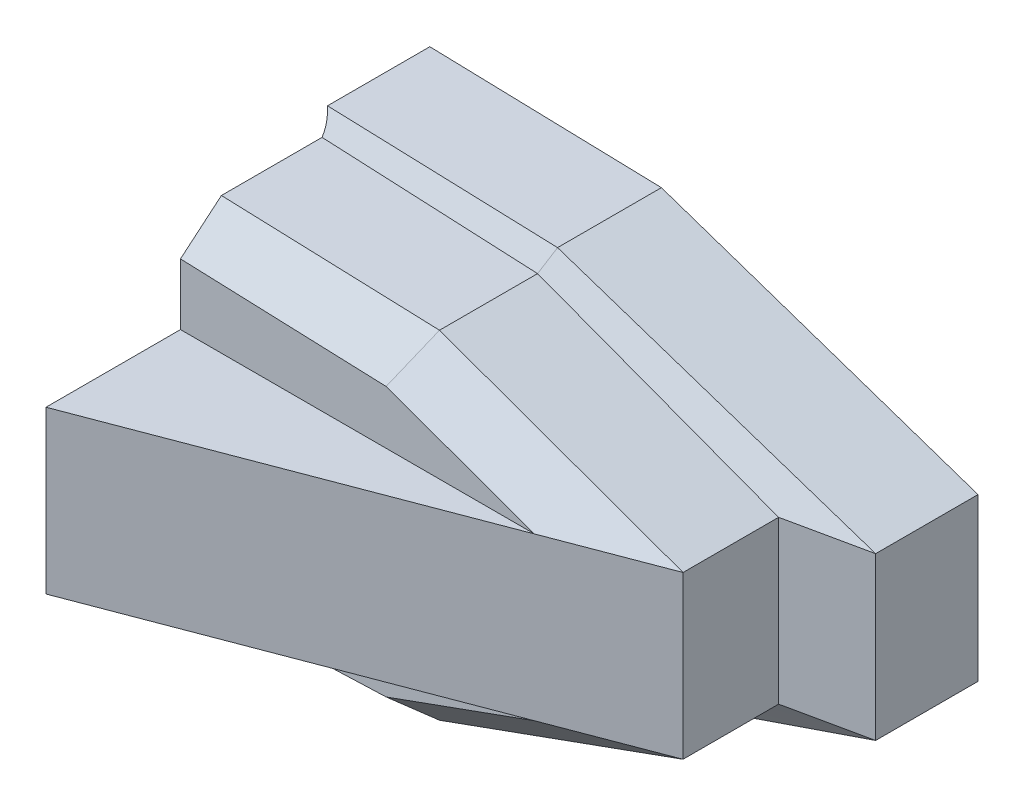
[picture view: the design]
ISO-10303-21;
HEADER;
FILE_DESCRIPTION(('STEP AP214'),'2;1');
FILE_NAME('part.step','',(''),(''),'','','');
FILE_SCHEMA(('AUTOMOTIVE_DESIGN { 1 0 10303 214 1 1 1 1 }'));
ENDSEC;
DATA;
#1=APPLICATION_CONTEXT('core data for automotive mechanical design processes');
#2=APPLICATION_PROTOCOL_DEFINITION('international standard','automotive_design',2000,#1);
#3=PRODUCT_CONTEXT('',#1,'mechanical');
#4=PRODUCT('Part','Part','',(#3));
#5=PRODUCT_RELATED_PRODUCT_CATEGORY('part','',(#4));
#6=PRODUCT_DEFINITION_FORMATION('','',#4);
#7=PRODUCT_DEFINITION_CONTEXT('part definition',#1,'design');
#8=PRODUCT_DEFINITION('design','',#6,#7);
#9=PRODUCT_DEFINITION_SHAPE('','',#8);
#10=(LENGTH_UNIT() NAMED_UNIT(*) SI_UNIT(.MILLI.,.METRE.));
#11=(NAMED_UNIT(*) PLANE_ANGLE_UNIT() SI_UNIT($,.RADIAN.));
#12=(NAMED_UNIT(*) SI_UNIT($,.STERADIAN.) SOLID_ANGLE_UNIT());
#13=UNCERTAINTY_MEASURE_WITH_UNIT(LENGTH_MEASURE(1.E-05),#10,'distance_accuracy_value','');
#14=(GEOMETRIC_REPRESENTATION_CONTEXT(3) GLOBAL_UNCERTAINTY_ASSIGNED_CONTEXT((#13)) GLOBAL_UNIT_ASSIGNED_CONTEXT((#10,
#11,#12)) REPRESENTATION_CONTEXT('',''));
#15=CARTESIAN_POINT('',(0.,0.,0.));
#16=DIRECTION('',(0.,0.,1.));
#17=DIRECTION('',(1.,0.,0.));
#18=AXIS2_PLACEMENT_3D('',#15,#16,#17);
#19=CARTESIAN_POINT('',(0.,158.06960654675,0.));
#20=DIRECTION('',(0.,-1.,0.));
#21=DIRECTION('',(0.,0.,-1.));
#22=AXIS2_PLACEMENT_3D('',#19,#20,#21);
#23=PLANE('',#22);
#24=DIRECTION('',(0.,0.,-1.));
#25=VECTOR('',#24,1.);
#26=CARTESIAN_POINT('',(1530.,158.06960654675,0.));
#27=LINE('',#26,#25);
#28=CARTESIAN_POINT('',(1530.,158.06960654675,762.78272385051));
#29=VERTEX_POINT('',#28);
#30=CARTESIAN_POINT('',(1530.,158.06960654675,500.));
#31=VERTEX_POINT('',#30);
#32=EDGE_CURVE('E68',#29,#31,#27,.T.);
#33=ORIENTED_EDGE('',*,*,#32,.F.);
#34=DIRECTION('',(-0.934788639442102,0.,0.355204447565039));
#35=VECTOR('',#34,1.);
#36=CARTESIAN_POINT('',(430.6727342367,158.06960654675,1180.509167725));
#37=LINE('',#36,#35);
#38=CARTESIAN_POINT('',(2221.563145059,158.06960654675,500.));
#39=VERTEX_POINT('',#38);
#40=EDGE_CURVE('E1070',#39,#29,#37,.T.);
#41=ORIENTED_EDGE('',*,*,#40,.F.);
#42=DIRECTION('',(1.,0.,0.));
#43=VECTOR('',#42,1.);
#44=CARTESIAN_POINT('',(0.,158.06960654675,500.));
#45=LINE('',#44,#43);
#46=EDGE_CURVE('E11',#31,#39,#45,.T.);
#47=ORIENTED_EDGE('',*,*,#46,.F.);
#48=EDGE_LOOP('',(#33,#41,#47));
#49=FACE_BOUND('',#48,.T.);
#50=ADVANCED_FACE('F46',(#49),#23,.F.);
#51=CARTESIAN_POINT('',(0.,0.,500.));
#52=DIRECTION('',(0.,0.,1.));
#53=DIRECTION('',(1.,0.,0.));
#54=AXIS2_PLACEMENT_3D('',#51,#52,#53);
#55=PLANE('',#54);
#56=ORIENTED_EDGE('',*,*,#46,.T.);
#57=DIRECTION('',(0.94052400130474,-0.339727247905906,0.));
#58=VECTOR('',#57,1.);
#59=CARTESIAN_POINT('',(2076.689498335,210.39950480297,500.));
#60=LINE('',#59,#58);
#61=CARTESIAN_POINT('',(1931.81585161,262.72940305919,500.));
#62=VERTEX_POINT('',#61);
#63=EDGE_CURVE('E858',#62,#39,#60,.T.);
#64=ORIENTED_EDGE('',*,*,#63,.F.);
#65=DIRECTION('',(0.999303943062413,-0.037304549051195,0.));
#66=VECTOR('',#65,1.);
#67=CARTESIAN_POINT('',(1530.,277.729403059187,500.));
#68=LINE('',#67,#66);
#69=CARTESIAN_POINT('',(1530.,277.72940305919,500.));
#70=VERTEX_POINT('',#69);
#71=EDGE_CURVE('E869',#70,#62,#68,.T.);
#72=ORIENTED_EDGE('',*,*,#71,.F.);
#73=DIRECTION('',(0.,-1.,0.));
#74=VECTOR('',#73,1.);
#75=CARTESIAN_POINT('',(1530.,-1.79233E-12,500.));
#76=LINE('',#75,#74);
#77=EDGE_CURVE('E59',#70,#31,#76,.T.);
#78=ORIENTED_EDGE('',*,*,#77,.T.);
#79=EDGE_LOOP('',(#56,#64,#72,#78));
#80=FACE_BOUND('',#79,.T.);
#81=ADVANCED_FACE('F404',(#80),#55,.T.);
#82=CARTESIAN_POINT('',(1517.2,-360.,450.));
#83=DIRECTION('',(-1.,0.,0.));
#84=DIRECTION('',(0.,0.,1.));
#85=AXIS2_PLACEMENT_3D('',#82,#83,#84);
#86=PLANE('',#85);
#87=DIRECTION('',(0.,0.707106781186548,0.707106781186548));
#88=VECTOR('',#87,1.);
#89=CARTESIAN_POINT('',(1517.2,135.,-44.99999999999));
#90=LINE('',#89,#88);
#91=CARTESIAN_POINT('',(1517.2,330.,150.));
#92=VERTEX_POINT('',#91);
#93=CARTESIAN_POINT('',(1517.2,380.08734023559,200.08734023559));
#94=VERTEX_POINT('',#93);
#95=EDGE_CURVE('E1067',#92,#94,#90,.T.);
#96=ORIENTED_EDGE('',*,*,#95,.T.);
#97=DIRECTION('',(3.57204538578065E-12,0.832000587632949,-0.554774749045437));
#98=VECTOR('',#97,1.);
#99=CARTESIAN_POINT('',(1517.2,380.087340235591,200.087340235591));
#100=LINE('',#99,#98);
#101=CARTESIAN_POINT('',(1517.2,380.34593331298,199.91491137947));
#102=VERTEX_POINT('',#101);
#103=EDGE_CURVE('E1074',#94,#102,#100,.T.);
#104=ORIENTED_EDGE('',*,*,#103,.T.);
#105=DIRECTION('',(0.,0.,1.));
#106=VECTOR('',#105,1.);
#107=CARTESIAN_POINT('',(1517.2,380.34593331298,450.));
#108=LINE('',#107,#106);
#109=CARTESIAN_POINT('',(1517.2,380.34593331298,0.));
#110=VERTEX_POINT('',#109);
#111=EDGE_CURVE('E875',#110,#102,#108,.T.);
#112=ORIENTED_EDGE('',*,*,#111,.F.);
#113=DIRECTION('',(0.,-1.,0.));
#114=VECTOR('',#113,1.);
#115=CARTESIAN_POINT('',(1517.2,-2.02662E-12,0.));
#116=LINE('',#115,#114);
#117=CARTESIAN_POINT('',(1517.2,330.,0.));
#118=VERTEX_POINT('',#117);
#119=EDGE_CURVE('E1058',#110,#118,#116,.T.);
#120=ORIENTED_EDGE('',*,*,#119,.T.);
#121=DIRECTION('',(0.,0.,1.));
#122=VECTOR('',#121,1.);
#123=CARTESIAN_POINT('',(1517.2,330.,450.));
#124=LINE('',#123,#122);
#125=EDGE_CURVE('E110',#118,#92,#124,.T.);
#126=ORIENTED_EDGE('',*,*,#125,.T.);
#127=EDGE_LOOP('',(#96,#104,#112,#120,#126));
#128=FACE_BOUND('',#127,.T.);
#129=ADVANCED_FACE('F409',(#128),#86,.T.);
#130=CARTESIAN_POINT('',(1529.95786937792,345.001483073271,420.));
#131=CARTESIAN_POINT('',(1529.95867019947,322.577950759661,446.66666666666));
#132=CARTESIAN_POINT('',(1529.95947102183,300.154418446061,473.33333333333));
#133=CARTESIAN_POINT('',(1529.96027184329,277.730886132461,500.));
#134=CARTESIAN_POINT('',(1672.01014789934,340.000988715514,420.));
#135=CARTESIAN_POINT('',(1669.31080918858,317.577456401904,446.66666666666));
#136=CARTESIAN_POINT('',(1666.61147047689,295.153924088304,473.33333333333));
#137=CARTESIAN_POINT('',(1663.91213176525,272.730391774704,500.));
#138=CARTESIAN_POINT('',(1814.06242642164,335.000494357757,420.));
#139=CARTESIAN_POINT('',(1808.66294817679,312.576962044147,446.66666666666));
#140=CARTESIAN_POINT('',(1803.26346993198,290.153429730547,473.33333333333));
#141=CARTESIAN_POINT('',(1797.8639916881,267.729897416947,500.));
#142=CARTESIAN_POINT('',(1956.114704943,330.,420.));
#143=CARTESIAN_POINT('',(1948.015087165,307.57646768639,446.66666666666));
#144=CARTESIAN_POINT('',(1939.915469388,285.15293537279,473.33333333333));
#145=CARTESIAN_POINT('',(1931.81585161,262.72940305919,500.));
#146=(BOUNDED_SURFACE() B_SPLINE_SURFACE(3,3,((#130,#131,#132,#133),(#134,#135,#136,#137),(#138,
#139,#140,#141),(#142,#143,#144,#145)),.UNSPECIFIED.,.F.,.F.,
.F.) B_SPLINE_SURFACE_WITH_KNOTS((4,4),(4,4),(0.0322699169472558,1.),(0.,1.),
.UNSPECIFIED.) GEOMETRIC_REPRESENTATION_ITEM() RATIONAL_B_SPLINE_SURFACE(((1.,1.,1.,1.),(1.,1.,
1.,1.),(1.,1.,1.,1.),(1.,1.,1.,1.))) REPRESENTATION_ITEM('') SURFACE());
#147=DIRECTION('',(0.226432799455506,0.626871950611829,-0.745492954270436));
#148=VECTOR('',#147,1.);
#149=CARTESIAN_POINT('',(1931.81585161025,262.729403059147,500.00000000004));
#150=LINE('',#149,#148);
#151=CARTESIAN_POINT('',(1956.114704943,329.99999999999,420.));
#152=VERTEX_POINT('',#151);
#153=EDGE_CURVE('E874',#62,#152,#150,.T.);
#154=DIRECTION('',(-0.999380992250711,0.0351799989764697,0.));
#155=VECTOR('',#154,1.);
#156=CARTESIAN_POINT('',(1956.114704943,329.999999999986,420.000000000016));
#157=LINE('',#156,#155);
#158=CARTESIAN_POINT('',(1530.,345.,420.));
#159=VERTEX_POINT('',#158);
#160=EDGE_CURVE('E871',#152,#159,#157,.T.);
#161=DIRECTION('',(0.,-0.643587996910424,0.765372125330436));
#162=VECTOR('',#161,1.);
#163=CARTESIAN_POINT('',(1530.,345.,420.));
#164=LINE('',#163,#162);
#165=EDGE_CURVE('E188',#159,#70,#164,.T.);
#166=ORIENTED_EDGE('',*,*,#71,.T.);
#167=ORIENTED_EDGE('',*,*,#153,.T.);
#168=ORIENTED_EDGE('',*,*,#160,.T.);
#169=ORIENTED_EDGE('',*,*,#165,.T.);
#170=EDGE_LOOP('',(#166,#167,#168,#169));
#171=FACE_BOUND('',#170,.T.);
#172=ADVANCED_FACE('F915',(#171),#146,.F.);
#173=CARTESIAN_POINT('',(2054.170903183,75.,563.60632371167));
#174=DIRECTION('',(0.355204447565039,0.,0.934788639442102));
#175=DIRECTION('',(0.,-1.,0.));
#176=AXIS2_PLACEMENT_3D('',#173,#174,#175);
#177=PLANE('',#176);
#178=DIRECTION('',(0.,1.,0.));
#179=VECTOR('',#178,1.);
#180=CARTESIAN_POINT('',(1530.,75.,762.78272385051));
#181=LINE('',#180,#179);
#182=CARTESIAN_POINT('',(1530.,-158.06960654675,762.78272385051));
#183=VERTEX_POINT('',#182);
#184=EDGE_CURVE('E774',#183,#29,#181,.T.);
#185=ORIENTED_EDGE('',*,*,#184,.F.);
#186=DIRECTION('',(-0.934788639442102,0.,0.355204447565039));
#187=VECTOR('',#186,1.);
#188=CARTESIAN_POINT('',(430.6727342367,-158.06960654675,1180.509167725));
#189=LINE('',#188,#187);
#190=CARTESIAN_POINT('',(2221.563145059,-158.06960654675,500.));
#191=VERTEX_POINT('',#190);
#192=EDGE_CURVE('E690',#191,#183,#189,.T.);
#193=ORIENTED_EDGE('',*,*,#192,.F.);
#194=DIRECTION('',(0.934788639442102,0.,-0.355204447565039));
#195=VECTOR('',#194,1.);
#196=CARTESIAN_POINT('',(2326.830817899,-158.06960654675,460.));
#197=LINE('',#196,#195);
#198=CARTESIAN_POINT('',(2432.09849074,-158.06960654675,420.));
#199=VERTEX_POINT('',#198);
#200=EDGE_CURVE('E724',#191,#199,#197,.T.);
#201=ORIENTED_EDGE('',*,*,#200,.T.);
#202=DIRECTION('',(0.,-1.,0.));
#203=VECTOR('',#202,1.);
#204=CARTESIAN_POINT('',(2432.09849074,74.999999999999,420.));
#205=LINE('',#204,#203);
#206=CARTESIAN_POINT('',(2432.09849074,158.06960654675,420.));
#207=VERTEX_POINT('',#206);
#208=EDGE_CURVE('E847',#207,#199,#205,.T.);
#209=ORIENTED_EDGE('',*,*,#208,.F.);
#210=DIRECTION('',(0.934788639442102,0.,-0.355204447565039));
#211=VECTOR('',#210,1.);
#212=CARTESIAN_POINT('',(2326.830817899,158.06960654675,460.));
#213=LINE('',#212,#211);
#214=EDGE_CURVE('E849',#39,#207,#213,.T.);
#215=ORIENTED_EDGE('',*,*,#214,.F.);
#216=ORIENTED_EDGE('',*,*,#40,.T.);
#217=EDGE_LOOP('',(#185,#193,#201,#209,#215,#216));
#218=FACE_BOUND('',#217,.T.);
#219=ADVANCED_FACE('F845',(#218),#177,.T.);
#220=CARTESIAN_POINT('',(0.,0.,0.));
#221=DIRECTION('',(0.,0.,1.));
#222=DIRECTION('',(1.,0.,0.));
#223=AXIS2_PLACEMENT_3D('',#220,#221,#222);
#224=PLANE('',#223);
#225=DIRECTION('',(0.,1.,0.));
#226=VECTOR('',#225,1.);
#227=CARTESIAN_POINT('',(2588.42339805,-191.9303934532,0.));
#228=LINE('',#227,#226);
#229=CARTESIAN_POINT('',(2588.42339805,-158.06960654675,0.));
#230=VERTEX_POINT('',#229);
#231=CARTESIAN_POINT('',(2588.42339805,158.06960654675,0.));
#232=VERTEX_POINT('',#231);
#233=EDGE_CURVE('E1040',#230,#232,#228,.T.);
#234=ORIENTED_EDGE('',*,*,#233,.F.);
#235=DIRECTION('',(0.946912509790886,0.321491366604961,0.));
#236=VECTOR('',#235,1.);
#237=CARTESIAN_POINT('',(2279.092211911,-263.09230371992,0.));
#238=LINE('',#237,#236);
#239=CARTESIAN_POINT('',(1969.761025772,-368.11500089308,0.));
#240=VERTEX_POINT('',#239);
#241=EDGE_CURVE('E705',#240,#230,#238,.T.);
#242=ORIENTED_EDGE('',*,*,#241,.F.);
#243=DIRECTION('',(-0.999634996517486,-0.0270161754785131,0.));
#244=VECTOR('',#243,1.);
#245=CARTESIAN_POINT('',(1752.008107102,-374.,0.));
#246=LINE('',#245,#244);
#247=CARTESIAN_POINT('',(1517.2,-380.34593331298,0.));
#248=VERTEX_POINT('',#247);
#249=EDGE_CURVE('E286',#240,#248,#246,.T.);
#250=ORIENTED_EDGE('',*,*,#249,.T.);
#251=DIRECTION('',(0.,1.,0.));
#252=VECTOR('',#251,1.);
#253=CARTESIAN_POINT('',(1517.2,2.02662E-12,0.));
#254=LINE('',#253,#252);
#255=CARTESIAN_POINT('',(1517.2,-330.,0.));
#256=VERTEX_POINT('',#255);
#257=EDGE_CURVE('E248',#248,#256,#254,.T.);
#258=ORIENTED_EDGE('',*,*,#257,.T.);
#259=DIRECTION('',(1.,0.,0.));
#260=VECTOR('',#259,1.);
#261=CARTESIAN_POINT('',(1480.,-330.,0.));
#262=LINE('',#261,#260);
#263=CARTESIAN_POINT('',(1530.,-330.,0.));
#264=VERTEX_POINT('',#263);
#265=EDGE_CURVE('E255',#256,#264,#262,.T.);
#266=ORIENTED_EDGE('',*,*,#265,.T.);
#267=DIRECTION('',(0.,-1.,0.));
#268=VECTOR('',#267,1.);
#269=CARTESIAN_POINT('',(1530.,-2.02662E-12,0.));
#270=LINE('',#269,#268);
#271=CARTESIAN_POINT('',(1530.,330.,0.));
#272=VERTEX_POINT('',#271);
#273=EDGE_CURVE('E175',#272,#264,#270,.T.);
#274=ORIENTED_EDGE('',*,*,#273,.F.);
#275=DIRECTION('',(1.,0.,0.));
#276=VECTOR('',#275,1.);
#277=CARTESIAN_POINT('',(1480.,330.,0.));
#278=LINE('',#277,#276);
#279=EDGE_CURVE('E211',#118,#272,#278,.T.);
#280=ORIENTED_EDGE('',*,*,#279,.F.);
#281=ORIENTED_EDGE('',*,*,#119,.F.);
#282=DIRECTION('',(-0.999634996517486,0.0270161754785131,0.));
#283=VECTOR('',#282,1.);
#284=CARTESIAN_POINT('',(1752.008107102,374.,0.));
#285=LINE('',#284,#283);
#286=CARTESIAN_POINT('',(1969.761025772,368.11500089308,0.));
#287=VERTEX_POINT('',#286);
#288=EDGE_CURVE('E856',#287,#110,#285,.T.);
#289=ORIENTED_EDGE('',*,*,#288,.F.);
#290=DIRECTION('',(0.946912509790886,-0.321491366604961,0.));
#291=VECTOR('',#290,1.);
#292=CARTESIAN_POINT('',(2279.092211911,263.09230371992,0.));
#293=LINE('',#292,#291);
#294=EDGE_CURVE('E1041',#287,#232,#293,.T.);
#295=ORIENTED_EDGE('',*,*,#294,.T.);
#296=EDGE_LOOP('',(#234,#242,#250,#258,#266,#274,#280,#281,#289,#295));
#297=FACE_BOUND('',#296,.T.);
#298=ADVANCED_FACE('F452',(#297),#224,.F.);
#299=CARTESIAN_POINT('',(2194.106597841,244.03480327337,420.));
#300=DIRECTION('',(0.253264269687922,0.701154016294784,0.666513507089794));
#301=DIRECTION('',(0.934788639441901,0.,-0.355204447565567));
#302=AXIS2_PLACEMENT_3D('',#299,#300,#301);
#303=PLANE('',#302);
#304=ORIENTED_EDGE('',*,*,#153,.F.);
#305=ORIENTED_EDGE('',*,*,#63,.T.);
#306=ORIENTED_EDGE('',*,*,#214,.T.);
#307=DIRECTION('',(-0.94052400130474,0.339727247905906,0.));
#308=VECTOR('',#307,1.);
#309=CARTESIAN_POINT('',(2194.106597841,244.03480327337,420.));
#310=LINE('',#309,#308);
#311=EDGE_CURVE('E853',#207,#152,#310,.T.);
#312=ORIENTED_EDGE('',*,*,#311,.T.);
#313=EDGE_LOOP('',(#304,#305,#306,#312));
#314=FACE_BOUND('',#313,.T.);
#315=ADVANCED_FACE('F448',(#314),#303,.T.);
#316=CARTESIAN_POINT('',(1752.008107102,374.,100.));
#317=DIRECTION('',(-0.0270161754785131,-0.999634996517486,0.));
#318=DIRECTION('',(-0.999634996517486,0.0270161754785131,0.));
#319=AXIS2_PLACEMENT_3D('',#316,#317,#318);
#320=PLANE('',#319);
#321=ORIENTED_EDGE('',*,*,#288,.T.);
#322=ORIENTED_EDGE('',*,*,#111,.T.);
#323=DIRECTION('',(0.999612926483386,-0.0270155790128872,0.00664497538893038));
#324=VECTOR('',#323,1.);
#325=CARTESIAN_POINT('',(1517.2,380.345933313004,199.914911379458));
#326=LINE('',#325,#324);
#327=CARTESIAN_POINT('',(1969.761025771,368.11500089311,202.92333273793));
#328=VERTEX_POINT('',#327);
#329=EDGE_CURVE('E200',#102,#328,#326,.T.);
#330=ORIENTED_EDGE('',*,*,#329,.T.);
#331=DIRECTION('',(0.,0.,1.));
#332=VECTOR('',#331,1.);
#333=CARTESIAN_POINT('',(1969.761025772,368.11500089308,100.));
#334=LINE('',#333,#332);
#335=EDGE_CURVE('E155',#287,#328,#334,.T.);
#336=ORIENTED_EDGE('',*,*,#335,.F.);
#337=EDGE_LOOP('',(#321,#322,#330,#336));
#338=FACE_BOUND('',#337,.T.);
#339=ADVANCED_FACE('F420',(#338),#320,.F.);
#340=CARTESIAN_POINT('',(1517.49815479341,345.440087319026,223.186637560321));
#341=CARTESIAN_POINT('',(1663.70367150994,340.293391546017,224.902202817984));
#342=CARTESIAN_POINT('',(1809.90918822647,335.146695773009,226.617768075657));
#343=CARTESIAN_POINT('',(1956.114704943,330.,228.33333333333));
#344=CARTESIAN_POINT('',(1517.36469762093,357.076290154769,215.42916900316));
#345=CARTESIAN_POINT('',(1665.13095793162,352.285860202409,216.90722371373));
#346=CARTESIAN_POINT('',(1812.89721824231,347.49543025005,218.3852784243));
#347=CARTESIAN_POINT('',(1960.663478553,342.70500029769,219.86333313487));
#348=CARTESIAN_POINT('',(1517.23124044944,368.712492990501,207.671700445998));
#349=CARTESIAN_POINT('',(1666.5582443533,364.278328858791,208.912244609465));
#350=CARTESIAN_POINT('',(1815.88524825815,359.844164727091,210.152788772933));
#351=CARTESIAN_POINT('',(1965.212252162,355.41000059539,211.3933329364));
#352=CARTESIAN_POINT('',(1517.09778327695,380.348695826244,199.914231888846));
#353=CARTESIAN_POINT('',(1667.98553077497,376.270797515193,200.917265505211));
#354=CARTESIAN_POINT('',(1818.87327827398,372.192899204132,201.920299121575));
#355=CARTESIAN_POINT('',(1969.761025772,368.11500089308,202.92333273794));
#356=(BOUNDED_SURFACE() B_SPLINE_SURFACE(3,3,((#340,#341,#342,#343),(#344,#345,#346,#347),(#348,
#349,#350,#351),(#352,#353,#354,#355)),.UNSPECIFIED.,.F.,.F.,
.F.) B_SPLINE_SURFACE_WITH_KNOTS((4,4),(4,4),(0.,1.),(0.00213433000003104,1.),
.UNSPECIFIED.) GEOMETRIC_REPRESENTATION_ITEM() RATIONAL_B_SPLINE_SURFACE(((1.,1.,1.,1.),(1.,1.,
1.,1.),(1.,1.,1.,1.),(1.,1.,1.,1.))) REPRESENTATION_ITEM('') SURFACE());
#357=CARTESIAN_POINT('',(1530.00000000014,344.99999999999,223.333333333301));
#358=CARTESIAN_POINT('',(1530.0003825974,345.615165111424,222.923130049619));
#359=CARTESIAN_POINT('',(1529.98952146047,346.23044366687,222.5130349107));
#360=CARTESIAN_POINT('',(1529.93410270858,347.774901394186,221.48402706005));
#361=CARTESIAN_POINT('',(1529.87516331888,348.703836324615,220.865483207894));
#362=CARTESIAN_POINT('',(1529.71118224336,350.505502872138,219.666378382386));
#363=CARTESIAN_POINT('',(1529.60898115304,351.378399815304,219.085675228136));
#364=CARTESIAN_POINT('',(1529.39035597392,352.90641193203,218.069462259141));
#365=CARTESIAN_POINT('',(1529.28355959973,353.56246037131,217.633255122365));
#366=CARTESIAN_POINT('',(1529.01004400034,355.061548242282,216.637024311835));
#367=CARTESIAN_POINT('',(1528.83492909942,355.903605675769,216.077802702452));
#368=CARTESIAN_POINT('',(1528.45605640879,357.527040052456,215.000095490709));
#369=CARTESIAN_POINT('',(1528.2548785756,358.30882400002,214.481311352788));
#370=CARTESIAN_POINT('',(1527.83239131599,359.811405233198,213.484478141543));
#371=CARTESIAN_POINT('',(1527.61345924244,360.532658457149,213.006108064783));
#372=CARTESIAN_POINT('',(1527.16336886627,361.914141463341,212.090120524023));
#373=CARTESIAN_POINT('',(1526.93439170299,362.574856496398,211.652160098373));
#374=CARTESIAN_POINT('',(1526.39841160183,364.034416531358,210.685277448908));
#375=CARTESIAN_POINT('',(1526.08531071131,364.831771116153,210.157474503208));
#376=CARTESIAN_POINT('',(1525.43004646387,366.399486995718,209.120318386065));
#377=CARTESIAN_POINT('',(1525.08863793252,367.170062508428,208.61081110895));
#378=CARTESIAN_POINT('',(1524.38022542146,368.683874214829,207.610232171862));
#379=CARTESIAN_POINT('',(1524.01393889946,369.427340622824,207.119000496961));
#380=CARTESIAN_POINT('',(1523.25914691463,370.886709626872,206.154982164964));
#381=CARTESIAN_POINT('',(1522.87132526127,371.602856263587,205.682029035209));
#382=CARTESIAN_POINT('',(1522.07673341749,373.00748392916,204.754571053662));
#383=CARTESIAN_POINT('',(1521.67061647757,373.69622059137,204.299893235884));
#384=CARTESIAN_POINT('',(1520.84258639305,375.046036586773,203.408991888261));
#385=CARTESIAN_POINT('',(1520.42129845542,375.707381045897,202.972588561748));
#386=CARTESIAN_POINT('',(1519.56595448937,377.002514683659,202.11823931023));
#387=CARTESIAN_POINT('',(1519.13249758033,377.636576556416,201.700106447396));
#388=CARTESIAN_POINT('',(1518.25570142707,378.877351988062,200.882312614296));
#389=CARTESIAN_POINT('',(1517.81293708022,379.484343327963,200.482456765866));
#390=CARTESIAN_POINT('',(1517.36024682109,380.086246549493,200.086246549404));
#391=B_SPLINE_CURVE_WITH_KNOTS('',3,(#357,#358,#359,#360,#361,#362,#363,#364,#365,#366,#367,
#368,#369,#370,#371,#372,#373,#374,#375,#376,#377,#378,#379,#380,#381,#382,#383,#384,#385,#386,
#387,#388,#389,#390),.UNSPECIFIED.,.F.,.F.,(4,2,2,2,2,2,2,2,2,2,2,2,2,2,2,2,4),(0.,
2.21815423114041,5.56968175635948,8.72882319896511,11.1135594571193,14.1903090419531,
17.0683700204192,19.7460189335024,22.220909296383,25.2386554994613,28.1925694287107,
31.0822905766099,33.9071087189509,36.6660166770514,39.3577627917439,41.9809015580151,
44.5338412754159),.UNSPECIFIED.);
#392=CARTESIAN_POINT('',(1530.,344.99999999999,223.33333333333));
#393=VERTEX_POINT('',#392);
#394=CARTESIAN_POINT('',(1517.360246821,380.08624654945,200.08624654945));
#395=VERTEX_POINT('',#394);
#396=EDGE_CURVE('E161',#393,#395,#391,.T.);
#397=DIRECTION('',(0.999312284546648,-0.0351775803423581,0.0117258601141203));
#398=VECTOR('',#397,1.);
#399=CARTESIAN_POINT('',(1530.,344.999999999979,223.333333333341));
#400=LINE('',#399,#398);
#401=CARTESIAN_POINT('',(1956.114704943,330.,228.33333333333));
#402=VERTEX_POINT('',#401);
#403=EDGE_CURVE('E166',#393,#402,#400,.T.);
#404=DIRECTION('',(0.285500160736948,0.797419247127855,-0.531612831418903));
#405=VECTOR('',#404,1.);
#406=CARTESIAN_POINT('',(1969.761025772,368.11500089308,202.92333273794));
#407=LINE('',#406,#405);
#408=EDGE_CURVE('E201',#402,#328,#407,.T.);
#409=DIRECTION('',(0.999953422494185,-0.00682469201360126,-0.00682469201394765));
#410=VECTOR('',#409,1.);
#411=CARTESIAN_POINT('',(1517.2,380.08734023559,200.087340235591));
#412=LINE('',#411,#410);
#413=EDGE_CURVE('E168',#94,#395,#412,.T.);
#414=ORIENTED_EDGE('',*,*,#396,.F.);
#415=ORIENTED_EDGE('',*,*,#403,.T.);
#416=ORIENTED_EDGE('',*,*,#408,.T.);
#417=ORIENTED_EDGE('',*,*,#329,.F.);
#418=ORIENTED_EDGE('',*,*,#103,.F.);
#419=ORIENTED_EDGE('',*,*,#413,.T.);
#420=EDGE_LOOP('',(#414,#415,#416,#417,#418,#419));
#421=FACE_BOUND('',#420,.T.);
#422=ADVANCED_FACE('F164',(#421),#356,.F.);
#423=CARTESIAN_POINT('',(1743.057352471,337.5,326.66666666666));
#424=DIRECTION('',(-0.0351799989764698,-0.999380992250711,0.));
#425=DIRECTION('',(-0.999380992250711,0.0351799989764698,0.));
#426=AXIS2_PLACEMENT_3D('',#423,#424,#425);
#427=PLANE('',#426);
#428=ORIENTED_EDGE('',*,*,#160,.F.);
#429=DIRECTION('',(0.,0.,1.));
#430=VECTOR('',#429,1.);
#431=CARTESIAN_POINT('',(1956.114704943,330.,420.));
#432=LINE('',#431,#430);
#433=EDGE_CURVE('E197',#402,#152,#432,.T.);
#434=ORIENTED_EDGE('',*,*,#433,.F.);
#435=ORIENTED_EDGE('',*,*,#403,.F.);
#436=DIRECTION('',(0.,0.,-1.));
#437=VECTOR('',#436,1.);
#438=CARTESIAN_POINT('',(1530.,345.,475.));
#439=LINE('',#438,#437);
#440=EDGE_CURVE('E183',#159,#393,#439,.T.);
#441=ORIENTED_EDGE('',*,*,#440,.F.);
#442=EDGE_LOOP('',(#428,#434,#435,#441));
#443=FACE_BOUND('',#442,.T.);
#444=ADVANCED_FACE('F195',(#443),#427,.F.);
#445=CARTESIAN_POINT('',(1956.114704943,330.,420.));
#446=DIRECTION('',(-0.339727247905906,-0.94052400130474,0.));
#447=DIRECTION('',(-0.94052400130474,0.339727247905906,0.));
#448=AXIS2_PLACEMENT_3D('',#445,#446,#447);
#449=PLANE('',#448);
#450=ORIENTED_EDGE('',*,*,#311,.F.);
#451=DIRECTION('',(0.,0.,1.));
#452=VECTOR('',#451,1.);
#453=CARTESIAN_POINT('',(2432.09849074,158.06960654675,0.));
#454=LINE('',#453,#452);
#455=CARTESIAN_POINT('',(2432.09849074,158.06960654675,233.33333333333));
#456=VERTEX_POINT('',#455);
#457=EDGE_CURVE('E135',#456,#207,#454,.T.);
#458=ORIENTED_EDGE('',*,*,#457,.F.);
#459=DIRECTION('',(0.940478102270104,-0.339710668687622,0.00987930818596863));
#460=VECTOR('',#459,1.);
#461=CARTESIAN_POINT('',(1956.114704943,330.,228.33333333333));
#462=LINE('',#461,#460);
#463=EDGE_CURVE('E878',#402,#456,#462,.T.);
#464=ORIENTED_EDGE('',*,*,#463,.F.);
#465=ORIENTED_EDGE('',*,*,#433,.T.);
#466=EDGE_LOOP('',(#450,#458,#464,#465));
#467=FACE_BOUND('',#466,.T.);
#468=ADVANCED_FACE('F440',(#467),#449,.F.);
#469=CARTESIAN_POINT('',(2432.09849074,158.06960654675,233.33333333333));
#470=CARTESIAN_POINT('',(2273.437228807,215.37973769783,231.66666666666));
#471=CARTESIAN_POINT('',(2114.775966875,272.68986884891,230.));
#472=CARTESIAN_POINT('',(1956.114704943,330.,228.33333333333));
#473=CARTESIAN_POINT('',(2484.206793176,158.06960654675,222.22222222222));
#474=CARTESIAN_POINT('',(2309.692354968,219.61473779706,221.43592585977));
#475=CARTESIAN_POINT('',(2135.17791676,281.15986904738,220.64962949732));
#476=CARTESIAN_POINT('',(1960.663478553,342.70500029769,219.86333313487));
#477=CARTESIAN_POINT('',(2536.315095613,158.06960654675,211.11111111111));
#478=CARTESIAN_POINT('',(2345.947481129,223.8497378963,211.20518505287));
#479=CARTESIAN_POINT('',(2155.579866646,289.62986924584,211.29925899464));
#480=CARTESIAN_POINT('',(1965.212252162,355.41000059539,211.3933329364));
#481=CARTESIAN_POINT('',(2588.42339805,158.06960654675,200.));
#482=CARTESIAN_POINT('',(2382.20260729,228.08473799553,200.97444424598));
#483=CARTESIAN_POINT('',(2175.981816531,298.0998694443,201.94888849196));
#484=CARTESIAN_POINT('',(1969.761025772,368.11500089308,202.92333273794));
#485=(BOUNDED_SURFACE() B_SPLINE_SURFACE(3,3,((#469,#470,#471,#472),(#473,#474,#475,#476),(#477,
#478,#479,#480),(#481,#482,#483,#484)),.UNSPECIFIED.,.F.,.F.,
.F.) B_SPLINE_SURFACE_WITH_KNOTS((4,4),(4,4),(0.,1.),(0.,1.),
.UNSPECIFIED.) GEOMETRIC_REPRESENTATION_ITEM() RATIONAL_B_SPLINE_SURFACE(((1.,1.,1.,1.),(1.,1.,
1.,1.),(1.,1.,1.,1.),(1.,1.,1.,1.))) REPRESENTATION_ITEM('') SURFACE());
#486=DIRECTION('',(-0.978013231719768,-2.8026593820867E-13,0.20854284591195));
#487=VECTOR('',#486,1.);
#488=CARTESIAN_POINT('',(2588.42339804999,158.069606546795,199.999999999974));
#489=LINE('',#488,#487);
#490=CARTESIAN_POINT('',(2588.42339805,158.06960654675,200.));
#491=VERTEX_POINT('',#490);
#492=EDGE_CURVE('E142',#491,#456,#489,.T.);
#493=DIRECTION('',(0.946903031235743,-0.321488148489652,-0.00447435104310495));
#494=VECTOR('',#493,1.);
#495=CARTESIAN_POINT('',(1969.76102577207,368.11500089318,202.923332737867));
#496=LINE('',#495,#494);
#497=EDGE_CURVE('E883',#328,#491,#496,.T.);
#498=ORIENTED_EDGE('',*,*,#492,.F.);
#499=ORIENTED_EDGE('',*,*,#497,.F.);
#500=ORIENTED_EDGE('',*,*,#408,.F.);
#501=ORIENTED_EDGE('',*,*,#463,.T.);
#502=EDGE_LOOP('',(#498,#499,#500,#501));
#503=FACE_BOUND('',#502,.T.);
#504=ADVANCED_FACE('F421',(#503),#485,.T.);
#505=CARTESIAN_POINT('',(2279.092211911,263.09230371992,103.96166636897));
#506=DIRECTION('',(0.321491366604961,0.946912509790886,0.));
#507=DIRECTION('',(0.,0.,-1.));
#508=AXIS2_PLACEMENT_3D('',#505,#506,#507);
#509=PLANE('',#508);
#510=ORIENTED_EDGE('',*,*,#294,.F.);
#511=ORIENTED_EDGE('',*,*,#335,.T.);
#512=ORIENTED_EDGE('',*,*,#497,.T.);
#513=DIRECTION('',(0.,0.,-1.));
#514=VECTOR('',#513,1.);
#515=CARTESIAN_POINT('',(2588.42339805,158.06960654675,200.));
#516=LINE('',#515,#514);
#517=EDGE_CURVE('E1043',#491,#232,#516,.T.);
#518=ORIENTED_EDGE('',*,*,#517,.T.);
#519=EDGE_LOOP('',(#510,#511,#512,#518));
#520=FACE_BOUND('',#519,.T.);
#521=ADVANCED_FACE('F329',(#520),#509,.T.);
#522=CARTESIAN_POINT('',(2588.42339805,-191.9303934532,200.));
#523=DIRECTION('',(-1.,0.,0.));
#524=DIRECTION('',(0.,0.,1.));
#525=AXIS2_PLACEMENT_3D('',#522,#523,#524);
#526=PLANE('',#525);
#527=DIRECTION('',(0.,1.,0.));
#528=VECTOR('',#527,1.);
#529=CARTESIAN_POINT('',(2588.42339805,-191.9303934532,200.));
#530=LINE('',#529,#528);
#531=CARTESIAN_POINT('',(2588.42339805,-158.06960654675,200.));
#532=VERTEX_POINT('',#531);
#533=EDGE_CURVE('E835',#532,#491,#530,.T.);
#534=ORIENTED_EDGE('',*,*,#533,.F.);
#535=DIRECTION('',(0.,0.,-1.));
#536=VECTOR('',#535,1.);
#537=CARTESIAN_POINT('',(2588.42339805,-158.06960654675,200.));
#538=LINE('',#537,#536);
#539=EDGE_CURVE('E700',#532,#230,#538,.T.);
#540=ORIENTED_EDGE('',*,*,#539,.T.);
#541=ORIENTED_EDGE('',*,*,#233,.T.);
#542=ORIENTED_EDGE('',*,*,#517,.F.);
#543=EDGE_LOOP('',(#534,#540,#541,#542));
#544=FACE_BOUND('',#543,.T.);
#545=ADVANCED_FACE('F485',(#544),#526,.F.);
#546=CARTESIAN_POINT('',(2432.09849074,-191.9303934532,233.33333333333));
#547=DIRECTION('',(-0.20854284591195,0.,-0.978013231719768));
#548=DIRECTION('',(-0.978013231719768,0.,0.20854284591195));
#549=AXIS2_PLACEMENT_3D('',#546,#547,#548);
#550=PLANE('',#549);
#551=DIRECTION('',(0.,1.,0.));
#552=VECTOR('',#551,1.);
#553=CARTESIAN_POINT('',(2432.09849074,-191.9303934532,233.33333333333));
#554=LINE('',#553,#552);
#555=CARTESIAN_POINT('',(2432.09849074,-158.06960654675,233.33333333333));
#556=VERTEX_POINT('',#555);
#557=EDGE_CURVE('E831',#556,#456,#554,.T.);
#558=ORIENTED_EDGE('',*,*,#557,.F.);
#559=DIRECTION('',(-0.978013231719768,2.8026593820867E-13,0.20854284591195));
#560=VECTOR('',#559,1.);
#561=CARTESIAN_POINT('',(2588.42339804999,-158.069606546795,199.999999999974));
#562=LINE('',#561,#560);
#563=EDGE_CURVE('E276',#532,#556,#562,.T.);
#564=ORIENTED_EDGE('',*,*,#563,.F.);
#565=ORIENTED_EDGE('',*,*,#533,.T.);
#566=ORIENTED_EDGE('',*,*,#492,.T.);
#567=EDGE_LOOP('',(#558,#564,#565,#566));
#568=FACE_BOUND('',#567,.T.);
#569=ADVANCED_FACE('F494',(#568),#550,.F.);
#570=CARTESIAN_POINT('',(2432.09849074,-191.9303934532,420.));
#571=DIRECTION('',(-1.,0.,0.));
#572=DIRECTION('',(0.,0.,1.));
#573=AXIS2_PLACEMENT_3D('',#570,#571,#572);
#574=PLANE('',#573);
#575=ORIENTED_EDGE('',*,*,#208,.T.);
#576=DIRECTION('',(0.,0.,1.));
#577=VECTOR('',#576,1.);
#578=CARTESIAN_POINT('',(2432.09849074,-158.06960654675,0.));
#579=LINE('',#578,#577);
#580=EDGE_CURVE('E272',#556,#199,#579,.T.);
#581=ORIENTED_EDGE('',*,*,#580,.F.);
#582=ORIENTED_EDGE('',*,*,#557,.T.);
#583=ORIENTED_EDGE('',*,*,#457,.T.);
#584=EDGE_LOOP('',(#575,#581,#582,#583));
#585=FACE_BOUND('',#584,.T.);
#586=ADVANCED_FACE('F503',(#585),#574,.F.);
#587=CARTESIAN_POINT('',(1530.,-360.,450.));
#588=DIRECTION('',(-1.,0.,0.));
#589=DIRECTION('',(0.,0.,1.));
#590=AXIS2_PLACEMENT_3D('',#587,#588,#589);
#591=PLANE('',#590);
#592=ORIENTED_EDGE('',*,*,#273,.T.);
#593=DIRECTION('',(0.,0.,-1.));
#594=VECTOR('',#593,1.);
#595=CARTESIAN_POINT('',(1530.,-330.,0.));
#596=LINE('',#595,#594);
#597=CARTESIAN_POINT('',(1530.,-330.,150.));
#598=VERTEX_POINT('',#597);
#599=EDGE_CURVE('E675',#598,#264,#596,.T.);
#600=ORIENTED_EDGE('',*,*,#599,.F.);
#601=DIRECTION('',(0.,-0.707106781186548,0.707106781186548));
#602=VECTOR('',#601,1.);
#603=CARTESIAN_POINT('',(1530.,-96.654762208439,-83.34523779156));
#604=LINE('',#603,#602);
#605=CARTESIAN_POINT('',(1530.,-345.,165.));
#606=VERTEX_POINT('',#605);
#607=EDGE_CURVE('E683',#598,#606,#604,.T.);
#608=ORIENTED_EDGE('',*,*,#607,.T.);
#609=DIRECTION('',(0.,0.,1.));
#610=VECTOR('',#609,1.);
#611=CARTESIAN_POINT('',(1530.,-345.,475.));
#612=LINE('',#611,#610);
#613=CARTESIAN_POINT('',(1530.,-344.99999999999,223.33333333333));
#614=VERTEX_POINT('',#613);
#615=EDGE_CURVE('E254',#606,#614,#612,.T.);
#616=ORIENTED_EDGE('',*,*,#615,.T.);
#617=DIRECTION('',(0.,0.,-1.));
#618=VECTOR('',#617,1.);
#619=CARTESIAN_POINT('',(1530.,-345.,475.));
#620=LINE('',#619,#618);
#621=CARTESIAN_POINT('',(1530.,-345.,420.));
#622=VERTEX_POINT('',#621);
#623=EDGE_CURVE('E350',#622,#614,#620,.T.);
#624=ORIENTED_EDGE('',*,*,#623,.F.);
#625=DIRECTION('',(0.,0.643587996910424,0.765372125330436));
#626=VECTOR('',#625,1.);
#627=CARTESIAN_POINT('',(1530.,-345.,420.));
#628=LINE('',#627,#626);
#629=CARTESIAN_POINT('',(1530.,-277.72940305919,500.));
#630=VERTEX_POINT('',#629);
#631=EDGE_CURVE('E282',#622,#630,#628,.T.);
#632=ORIENTED_EDGE('',*,*,#631,.T.);
#633=DIRECTION('',(0.,1.,0.));
#634=VECTOR('',#633,1.);
#635=CARTESIAN_POINT('',(1530.,1.79233E-12,500.));
#636=LINE('',#635,#634);
#637=CARTESIAN_POINT('',(1530.,-158.06960654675,500.));
#638=VERTEX_POINT('',#637);
#639=EDGE_CURVE('E232',#630,#638,#636,.T.);
#640=ORIENTED_EDGE('',*,*,#639,.T.);
#641=DIRECTION('',(0.,0.,-1.));
#642=VECTOR('',#641,1.);
#643=CARTESIAN_POINT('',(1530.,-158.06960654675,0.));
#644=LINE('',#643,#642);
#645=EDGE_CURVE('E277',#183,#638,#644,.T.);
#646=ORIENTED_EDGE('',*,*,#645,.F.);
#647=ORIENTED_EDGE('',*,*,#184,.T.);
#648=ORIENTED_EDGE('',*,*,#32,.T.);
#649=ORIENTED_EDGE('',*,*,#77,.F.);
#650=ORIENTED_EDGE('',*,*,#165,.F.);
#651=ORIENTED_EDGE('',*,*,#440,.T.);
#652=DIRECTION('',(0.,0.,1.));
#653=VECTOR('',#652,1.);
#654=CARTESIAN_POINT('',(1530.,345.,475.));
#655=LINE('',#654,#653);
#656=CARTESIAN_POINT('',(1530.,345.,165.));
#657=VERTEX_POINT('',#656);
#658=EDGE_CURVE('E176',#657,#393,#655,.T.);
#659=ORIENTED_EDGE('',*,*,#658,.F.);
#660=DIRECTION('',(0.,0.707106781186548,0.707106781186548));
#661=VECTOR('',#660,1.);
#662=CARTESIAN_POINT('',(1530.,96.654762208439,-83.34523779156));
#663=LINE('',#662,#661);
#664=CARTESIAN_POINT('',(1530.,330.,150.));
#665=VERTEX_POINT('',#664);
#666=EDGE_CURVE('E222',#665,#657,#663,.T.);
#667=ORIENTED_EDGE('',*,*,#666,.F.);
#668=DIRECTION('',(0.,0.,-1.));
#669=VECTOR('',#668,1.);
#670=CARTESIAN_POINT('',(1530.,330.,0.));
#671=LINE('',#670,#669);
#672=EDGE_CURVE('E193',#665,#272,#671,.T.);
#673=ORIENTED_EDGE('',*,*,#672,.T.);
#674=EDGE_LOOP('',(#592,#600,#608,#616,#624,#632,#640,#646,#647,#648,#649,#650,#651,#659,#667,#673));
#675=FACE_BOUND('',#674,.T.);
#676=ADVANCED_FACE('F185',(#675),#591,.T.);
#677=CARTESIAN_POINT('',(1517.21004844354,380.285286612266,-99550.));
#678=CARTESIAN_POINT('',(1525.68566392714,369.090983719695,-99550.));
#679=CARTESIAN_POINT('',(1530.00723404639,357.168511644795,-99550.));
#680=CARTESIAN_POINT('',(1530.00000000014,344.99999999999,-99550.));
#681=(BOUNDED_CURVE() B_SPLINE_CURVE(3,(#677,#678,#679,#680),.UNSPECIFIED.,.F.,
.F.) B_SPLINE_CURVE_WITH_KNOTS((4,4),(0.,1.),
.UNSPECIFIED.) CURVE() GEOMETRIC_REPRESENTATION_ITEM() RATIONAL_B_SPLINE_CURVE((1.,
0.986520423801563,0.986520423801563,1.)) REPRESENTATION_ITEM(''));
#682=DIRECTION('',(0.,0.,1.));
#683=VECTOR('',#682,1.);
#684=SURFACE_OF_LINEAR_EXTRUSION('',#681,#683);
#685=ORIENTED_EDGE('',*,*,#396,.T.);
#686=CARTESIAN_POINT('',(1369.98303290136,344.999999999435,164.99999999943));
#687=DIRECTION('',(0.,-0.707106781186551,0.707106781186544));
#688=DIRECTION('',(0.999999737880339,0.000511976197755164,0.000511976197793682));
#689=AXIS2_PLACEMENT_3D('',#686,#687,#688);
#690=ELLIPSE('',#689,160.016991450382,127.279203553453);
#691=EDGE_CURVE('E203',#657,#395,#690,.T.);
#692=ORIENTED_EDGE('',*,*,#691,.F.);
#693=ORIENTED_EDGE('',*,*,#658,.T.);
#694=EDGE_LOOP('',(#685,#692,#693));
#695=FACE_BOUND('',#694,.T.);
#696=ADVANCED_FACE('F48',(#695),#684,.T.);
#697=CARTESIAN_POINT('',(1480.,330.,0.));
#698=DIRECTION('',(0.,-1.,0.));
#699=DIRECTION('',(0.,0.,-1.));
#700=AXIS2_PLACEMENT_3D('',#697,#698,#699);
#701=PLANE('',#700);
#702=DIRECTION('',(-1.,0.,0.));
#703=VECTOR('',#702,1.);
#704=CARTESIAN_POINT('',(885.,330.,150.));
#705=LINE('',#704,#703);
#706=EDGE_CURVE('E205',#665,#92,#705,.T.);
#707=ORIENTED_EDGE('',*,*,#706,.T.);
#708=ORIENTED_EDGE('',*,*,#125,.F.);
#709=ORIENTED_EDGE('',*,*,#279,.T.);
#710=ORIENTED_EDGE('',*,*,#672,.F.);
#711=EDGE_LOOP('',(#707,#708,#709,#710));
#712=FACE_BOUND('',#711,.T.);
#713=ADVANCED_FACE('F459',(#712),#701,.T.);
#714=CARTESIAN_POINT('',(885.,96.654762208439,-83.34523779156));
#715=DIRECTION('',(0.,-0.707106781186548,0.707106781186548));
#716=DIRECTION('',(-1.,0.,0.));
#717=AXIS2_PLACEMENT_3D('',#714,#715,#716);
#718=PLANE('',#717);
#719=ORIENTED_EDGE('',*,*,#413,.F.);
#720=ORIENTED_EDGE('',*,*,#95,.F.);
#721=ORIENTED_EDGE('',*,*,#706,.F.);
#722=ORIENTED_EDGE('',*,*,#666,.T.);
#723=ORIENTED_EDGE('',*,*,#691,.T.);
#724=EDGE_LOOP('',(#719,#720,#721,#722,#723));
#725=FACE_BOUND('',#724,.T.);
#726=ADVANCED_FACE('F456',(#725),#718,.T.);
#727=CARTESIAN_POINT('',(0.,-158.06960654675,0.));
#728=DIRECTION('',(0.,1.,0.));
#729=DIRECTION('',(0.,0.,-1.));
#730=AXIS2_PLACEMENT_3D('',#727,#728,#729);
#731=PLANE('',#730);
#732=ORIENTED_EDGE('',*,*,#645,.T.);
#733=DIRECTION('',(1.,0.,0.));
#734=VECTOR('',#733,1.);
#735=CARTESIAN_POINT('',(0.,-158.06960654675,500.));
#736=LINE('',#735,#734);
#737=EDGE_CURVE('E223',#638,#191,#736,.T.);
#738=ORIENTED_EDGE('',*,*,#737,.T.);
#739=ORIENTED_EDGE('',*,*,#192,.T.);
#740=EDGE_LOOP('',(#732,#738,#739));
#741=FACE_BOUND('',#740,.T.);
#742=ADVANCED_FACE('F458',(#741),#731,.F.);
#743=CARTESIAN_POINT('',(0.,0.,500.));
#744=DIRECTION('',(0.,0.,1.));
#745=DIRECTION('',(1.,0.,0.));
#746=AXIS2_PLACEMENT_3D('',#743,#744,#745);
#747=PLANE('',#746);
#748=ORIENTED_EDGE('',*,*,#737,.F.);
#749=ORIENTED_EDGE('',*,*,#639,.F.);
#750=DIRECTION('',(0.999303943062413,0.037304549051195,0.));
#751=VECTOR('',#750,1.);
#752=CARTESIAN_POINT('',(1530.,-277.729403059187,500.));
#753=LINE('',#752,#751);
#754=CARTESIAN_POINT('',(1931.81585161,-262.72940305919,500.));
#755=VERTEX_POINT('',#754);
#756=EDGE_CURVE('E266',#630,#755,#753,.T.);
#757=ORIENTED_EDGE('',*,*,#756,.T.);
#758=DIRECTION('',(0.94052400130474,0.339727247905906,0.));
#759=VECTOR('',#758,1.);
#760=CARTESIAN_POINT('',(2076.689498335,-210.39950480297,500.));
#761=LINE('',#760,#759);
#762=EDGE_CURVE('E709',#755,#191,#761,.T.);
#763=ORIENTED_EDGE('',*,*,#762,.T.);
#764=EDGE_LOOP('',(#748,#749,#757,#763));
#765=FACE_BOUND('',#764,.T.);
#766=ADVANCED_FACE('F365',(#765),#747,.T.);
#767=CARTESIAN_POINT('',(1517.2,360.,450.));
#768=DIRECTION('',(-1.,0.,0.));
#769=DIRECTION('',(0.,0.,1.));
#770=AXIS2_PLACEMENT_3D('',#767,#768,#769);
#771=PLANE('',#770);
#772=DIRECTION('',(0.,-0.707106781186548,0.707106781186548));
#773=VECTOR('',#772,1.);
#774=CARTESIAN_POINT('',(1517.2,-135.,-44.99999999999));
#775=LINE('',#774,#773);
#776=CARTESIAN_POINT('',(1517.2,-330.,150.));
#777=VERTEX_POINT('',#776);
#778=CARTESIAN_POINT('',(1517.2,-380.08734023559,200.08734023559));
#779=VERTEX_POINT('',#778);
#780=EDGE_CURVE('E244',#777,#779,#775,.T.);
#781=ORIENTED_EDGE('',*,*,#780,.F.);
#782=DIRECTION('',(0.,0.,1.));
#783=VECTOR('',#782,1.);
#784=CARTESIAN_POINT('',(1517.2,-330.,450.));
#785=LINE('',#784,#783);
#786=EDGE_CURVE('E270',#256,#777,#785,.T.);
#787=ORIENTED_EDGE('',*,*,#786,.F.);
#788=ORIENTED_EDGE('',*,*,#257,.F.);
#789=DIRECTION('',(0.,0.,1.));
#790=VECTOR('',#789,1.);
#791=CARTESIAN_POINT('',(1517.2,-380.34593331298,450.));
#792=LINE('',#791,#790);
#793=CARTESIAN_POINT('',(1517.2,-380.34593331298,199.91491137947));
#794=VERTEX_POINT('',#793);
#795=EDGE_CURVE('E264',#248,#794,#792,.T.);
#796=ORIENTED_EDGE('',*,*,#795,.T.);
#797=DIRECTION('',(3.57204538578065E-12,-0.832000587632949,-0.554774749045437));
#798=VECTOR('',#797,1.);
#799=CARTESIAN_POINT('',(1517.2,-380.087340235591,200.087340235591));
#800=LINE('',#799,#798);
#801=EDGE_CURVE('E256',#779,#794,#800,.T.);
#802=ORIENTED_EDGE('',*,*,#801,.F.);
#803=EDGE_LOOP('',(#781,#787,#788,#796,#802));
#804=FACE_BOUND('',#803,.T.);
#805=ADVANCED_FACE('F547',(#804),#771,.T.);
#806=CARTESIAN_POINT('',(1529.95786937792,-345.001483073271,420.));
#807=CARTESIAN_POINT('',(1529.95867019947,-322.577950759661,446.66666666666));
#808=CARTESIAN_POINT('',(1529.95947102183,-300.154418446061,473.33333333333));
#809=CARTESIAN_POINT('',(1529.96027184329,-277.730886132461,500.));
#810=CARTESIAN_POINT('',(1672.01014789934,-340.000988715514,420.));
#811=CARTESIAN_POINT('',(1669.31080918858,-317.577456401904,446.66666666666));
#812=CARTESIAN_POINT('',(1666.61147047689,-295.153924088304,473.33333333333));
#813=CARTESIAN_POINT('',(1663.91213176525,-272.730391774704,500.));
#814=CARTESIAN_POINT('',(1814.06242642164,-335.000494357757,420.));
#815=CARTESIAN_POINT('',(1808.66294817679,-312.576962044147,446.66666666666));
#816=CARTESIAN_POINT('',(1803.26346993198,-290.153429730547,473.33333333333));
#817=CARTESIAN_POINT('',(1797.8639916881,-267.729897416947,500.));
#818=CARTESIAN_POINT('',(1956.114704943,-330.,420.));
#819=CARTESIAN_POINT('',(1948.015087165,-307.57646768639,446.66666666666));
#820=CARTESIAN_POINT('',(1939.915469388,-285.15293537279,473.33333333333));
#821=CARTESIAN_POINT('',(1931.81585161,-262.72940305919,500.));
#822=(BOUNDED_SURFACE() B_SPLINE_SURFACE(3,3,((#806,#807,#808,#809),(#810,#811,#812,#813),(#814,
#815,#816,#817),(#818,#819,#820,#821)),.UNSPECIFIED.,.F.,.F.,
.F.) B_SPLINE_SURFACE_WITH_KNOTS((4,4),(4,4),(0.0322699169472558,1.),(0.,1.),
.UNSPECIFIED.) GEOMETRIC_REPRESENTATION_ITEM() RATIONAL_B_SPLINE_SURFACE(((1.,1.,1.,1.),(1.,1.,
1.,1.),(1.,1.,1.,1.),(1.,1.,1.,1.))) REPRESENTATION_ITEM('') SURFACE());
#823=DIRECTION('',(-0.999380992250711,-0.0351799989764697,0.));
#824=VECTOR('',#823,1.);
#825=CARTESIAN_POINT('',(1956.114704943,-329.999999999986,420.000000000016));
#826=LINE('',#825,#824);
#827=CARTESIAN_POINT('',(1956.114704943,-329.99999999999,420.));
#828=VERTEX_POINT('',#827);
#829=EDGE_CURVE('E278',#828,#622,#826,.T.);
#830=DIRECTION('',(0.226432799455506,-0.626871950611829,-0.745492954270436));
#831=VECTOR('',#830,1.);
#832=CARTESIAN_POINT('',(1931.81585161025,-262.729403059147,500.00000000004));
#833=LINE('',#832,#831);
#834=EDGE_CURVE('E271',#755,#828,#833,.T.);
#835=ORIENTED_EDGE('',*,*,#756,.F.);
#836=ORIENTED_EDGE('',*,*,#631,.F.);
#837=ORIENTED_EDGE('',*,*,#829,.F.);
#838=ORIENTED_EDGE('',*,*,#834,.F.);
#839=EDGE_LOOP('',(#835,#836,#837,#838));
#840=FACE_BOUND('',#839,.T.);
#841=ADVANCED_FACE('F390',(#840),#822,.T.);
#842=CARTESIAN_POINT('',(2194.106597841,-244.03480327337,420.));
#843=DIRECTION('',(0.253264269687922,-0.701154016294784,0.666513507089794));
#844=DIRECTION('',(0.934788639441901,0.,-0.355204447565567));
#845=AXIS2_PLACEMENT_3D('',#842,#843,#844);
#846=PLANE('',#845);
#847=ORIENTED_EDGE('',*,*,#834,.T.);
#848=DIRECTION('',(-0.94052400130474,-0.339727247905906,0.));
#849=VECTOR('',#848,1.);
#850=CARTESIAN_POINT('',(2194.106597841,-244.03480327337,420.));
#851=LINE('',#850,#849);
#852=EDGE_CURVE('E305',#199,#828,#851,.T.);
#853=ORIENTED_EDGE('',*,*,#852,.F.);
#854=ORIENTED_EDGE('',*,*,#200,.F.);
#855=ORIENTED_EDGE('',*,*,#762,.F.);
#856=EDGE_LOOP('',(#847,#853,#854,#855));
#857=FACE_BOUND('',#856,.T.);
#858=ADVANCED_FACE('F386',(#857),#846,.T.);
#859=CARTESIAN_POINT('',(1752.008107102,-374.,100.));
#860=DIRECTION('',(-0.0270161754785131,0.999634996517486,0.));
#861=DIRECTION('',(-0.999634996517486,-0.0270161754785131,0.));
#862=AXIS2_PLACEMENT_3D('',#859,#860,#861);
#863=PLANE('',#862);
#864=ORIENTED_EDGE('',*,*,#249,.F.);
#865=DIRECTION('',(0.,0.,1.));
#866=VECTOR('',#865,1.);
#867=CARTESIAN_POINT('',(1969.761025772,-368.11500089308,100.));
#868=LINE('',#867,#866);
#869=CARTESIAN_POINT('',(1969.761025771,-368.11500089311,202.92333273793));
#870=VERTEX_POINT('',#869);
#871=EDGE_CURVE('E292',#240,#870,#868,.T.);
#872=ORIENTED_EDGE('',*,*,#871,.T.);
#873=DIRECTION('',(0.999612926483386,0.0270155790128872,0.00664497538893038));
#874=VECTOR('',#873,1.);
#875=CARTESIAN_POINT('',(1517.2,-380.345933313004,199.914911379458));
#876=LINE('',#875,#874);
#877=EDGE_CURVE('E260',#794,#870,#876,.T.);
#878=ORIENTED_EDGE('',*,*,#877,.F.);
#879=ORIENTED_EDGE('',*,*,#795,.F.);
#880=EDGE_LOOP('',(#864,#872,#878,#879));
#881=FACE_BOUND('',#880,.T.);
#882=ADVANCED_FACE('F364',(#881),#863,.F.);
#883=CARTESIAN_POINT('',(1517.49815479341,-345.440087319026,223.186637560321));
#884=CARTESIAN_POINT('',(1663.70367150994,-340.293391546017,224.902202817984));
#885=CARTESIAN_POINT('',(1809.90918822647,-335.146695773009,226.617768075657));
#886=CARTESIAN_POINT('',(1956.114704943,-330.,228.33333333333));
#887=CARTESIAN_POINT('',(1517.36469762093,-357.076290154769,215.42916900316));
#888=CARTESIAN_POINT('',(1665.13095793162,-352.285860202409,216.90722371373));
#889=CARTESIAN_POINT('',(1812.89721824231,-347.49543025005,218.3852784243));
#890=CARTESIAN_POINT('',(1960.663478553,-342.70500029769,219.86333313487));
#891=CARTESIAN_POINT('',(1517.23124044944,-368.712492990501,207.671700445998));
#892=CARTESIAN_POINT('',(1666.5582443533,-364.278328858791,208.912244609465));
#893=CARTESIAN_POINT('',(1815.88524825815,-359.844164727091,210.152788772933));
#894=CARTESIAN_POINT('',(1965.212252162,-355.41000059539,211.3933329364));
#895=CARTESIAN_POINT('',(1517.09778327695,-380.348695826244,199.914231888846));
#896=CARTESIAN_POINT('',(1667.98553077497,-376.270797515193,200.917265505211));
#897=CARTESIAN_POINT('',(1818.87327827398,-372.192899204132,201.920299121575));
#898=CARTESIAN_POINT('',(1969.761025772,-368.11500089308,202.92333273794));
#899=(BOUNDED_SURFACE() B_SPLINE_SURFACE(3,3,((#883,#884,#885,#886),(#887,#888,#889,#890),(#891,
#892,#893,#894),(#895,#896,#897,#898)),.UNSPECIFIED.,.F.,.F.,
.F.) B_SPLINE_SURFACE_WITH_KNOTS((4,4),(4,4),(0.,1.),(0.00213433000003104,1.),
.UNSPECIFIED.) GEOMETRIC_REPRESENTATION_ITEM() RATIONAL_B_SPLINE_SURFACE(((1.,1.,1.,1.),(1.,1.,
1.,1.),(1.,1.,1.,1.),(1.,1.,1.,1.))) REPRESENTATION_ITEM('') SURFACE());
#900=CARTESIAN_POINT('',(1530.00000000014,-344.999999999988,223.333333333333));
#901=CARTESIAN_POINT('',(1530.00048572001,-345.761013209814,222.825985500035));
#902=CARTESIAN_POINT('',(1529.98390892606,-346.522129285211,222.318769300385));
#903=CARTESIAN_POINT('',(1529.91657167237,-348.044101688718,221.304908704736));
#904=CARTESIAN_POINT('',(1529.86578411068,-348.804957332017,220.79826508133));
#905=CARTESIAN_POINT('',(1529.72982008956,-350.326363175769,219.785580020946));
#906=CARTESIAN_POINT('',(1529.64457008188,-351.086909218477,219.279542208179));
#907=CARTESIAN_POINT('',(1529.43952719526,-352.607651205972,218.268097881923));
#908=CARTESIAN_POINT('',(1529.31961416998,-353.367836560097,217.762699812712));
#909=CARTESIAN_POINT('',(1529.04507873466,-354.887816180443,216.752561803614));
#910=CARTESIAN_POINT('',(1528.89029010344,-355.647590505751,216.247837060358));
#911=CARTESIAN_POINT('',(1528.5458403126,-357.166710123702,215.239070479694));
#912=CARTESIAN_POINT('',(1528.35596819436,-357.926023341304,214.735052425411));
#913=CARTESIAN_POINT('',(1527.94118722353,-359.444185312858,213.727722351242));
#914=CARTESIAN_POINT('',(1527.71602471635,-360.202987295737,213.224444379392));
#915=CARTESIAN_POINT('',(1527.2304949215,-361.720095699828,212.218614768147));
#916=CARTESIAN_POINT('',(1526.96983394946,-362.478338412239,211.716108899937));
#917=CARTESIAN_POINT('',(1526.42824266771,-363.953184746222,210.739079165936));
#918=CARTESIAN_POINT('',(1526.14872682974,-364.670141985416,210.264303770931));
#919=CARTESIAN_POINT('',(1525.55888216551,-366.09999903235,209.317800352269));
#920=CARTESIAN_POINT('',(1525.24838433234,-366.812851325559,208.846105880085));
#921=CARTESIAN_POINT('',(1524.5964488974,-368.234472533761,207.905781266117));
#922=CARTESIAN_POINT('',(1524.25481187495,-368.943178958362,207.437194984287));
#923=CARTESIAN_POINT('',(1523.54047208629,-370.356488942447,206.503099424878));
#924=CARTESIAN_POINT('',(1523.16754171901,-371.061013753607,206.037645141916));
#925=CARTESIAN_POINT('',(1522.39048898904,-372.465941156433,205.109826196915));
#926=CARTESIAN_POINT('',(1521.98611339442,-373.166247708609,204.64752832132));
#927=CARTESIAN_POINT('',(1521.14604396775,-374.562722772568,203.726032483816));
#928=CARTESIAN_POINT('',(1520.71007407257,-375.258777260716,203.266913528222));
#929=CARTESIAN_POINT('',(1519.80668795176,-376.646726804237,202.351789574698));
#930=CARTESIAN_POINT('',(1519.33897577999,-377.338489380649,201.895876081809));
#931=CARTESIAN_POINT('',(1518.37198109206,-378.717859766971,200.987159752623));
#932=CARTESIAN_POINT('',(1517.87238585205,-379.405316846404,200.534460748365));
#933=CARTESIAN_POINT('',(1517.36024682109,-380.086246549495,200.086246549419));
#934=B_SPLINE_CURVE_WITH_KNOTS('',3,(#900,#901,#902,#903,#904,#905,#906,#907,#908,#909,#910,
#911,#912,#913,#914,#915,#916,#917,#918,#919,#920,#921,#922,#923,#924,#925,#926,#927,#928,#929,
#930,#931,#932,#933),.UNSPECIFIED.,.F.,.F.,(4,2,2,2,2,2,2,2,2,2,2,2,2,2,2,2,4),(0.,
2.74372870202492,5.4896335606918,8.24142981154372,11.0028809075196,13.7777827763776,
16.5699479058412,19.3831895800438,22.2213065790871,24.933368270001,27.6611298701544,
30.4077866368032,33.1765175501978,35.9704742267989,38.7927705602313,41.6464732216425,
44.5345931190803),.UNSPECIFIED.);
#935=CARTESIAN_POINT('',(1517.360246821,-380.08624654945,200.08624654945));
#936=VERTEX_POINT('',#935);
#937=EDGE_CURVE('E345',#614,#936,#934,.T.);
#938=DIRECTION('',(0.999953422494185,0.00682469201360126,-0.00682469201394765));
#939=VECTOR('',#938,1.);
#940=CARTESIAN_POINT('',(1517.2,-380.08734023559,200.087340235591));
#941=LINE('',#940,#939);
#942=EDGE_CURVE('E301',#779,#936,#941,.T.);
#943=DIRECTION('',(0.285500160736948,-0.797419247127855,-0.531612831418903));
#944=VECTOR('',#943,1.);
#945=CARTESIAN_POINT('',(1969.761025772,-368.11500089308,202.92333273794));
#946=LINE('',#945,#944);
#947=CARTESIAN_POINT('',(1956.114704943,-330.,228.33333333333));
#948=VERTEX_POINT('',#947);
#949=EDGE_CURVE('E297',#948,#870,#946,.T.);
#950=DIRECTION('',(0.999312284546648,0.0351775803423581,0.0117258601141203));
#951=VECTOR('',#950,1.);
#952=CARTESIAN_POINT('',(1530.,-344.999999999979,223.333333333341));
#953=LINE('',#952,#951);
#954=EDGE_CURVE('E265',#614,#948,#953,.T.);
#955=ORIENTED_EDGE('',*,*,#937,.T.);
#956=ORIENTED_EDGE('',*,*,#942,.F.);
#957=ORIENTED_EDGE('',*,*,#801,.T.);
#958=ORIENTED_EDGE('',*,*,#877,.T.);
#959=ORIENTED_EDGE('',*,*,#949,.F.);
#960=ORIENTED_EDGE('',*,*,#954,.F.);
#961=EDGE_LOOP('',(#955,#956,#957,#958,#959,#960));
#962=FACE_BOUND('',#961,.T.);
#963=ADVANCED_FACE('F352',(#962),#899,.T.);
#964=CARTESIAN_POINT('',(1743.057352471,-337.5,326.66666666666));
#965=DIRECTION('',(-0.0351799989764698,0.999380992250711,0.));
#966=DIRECTION('',(-0.999380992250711,-0.0351799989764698,0.));
#967=AXIS2_PLACEMENT_3D('',#964,#965,#966);
#968=PLANE('',#967);
#969=ORIENTED_EDGE('',*,*,#829,.T.);
#970=ORIENTED_EDGE('',*,*,#623,.T.);
#971=ORIENTED_EDGE('',*,*,#954,.T.);
#972=DIRECTION('',(0.,0.,1.));
#973=VECTOR('',#972,1.);
#974=CARTESIAN_POINT('',(1956.114704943,-330.,420.));
#975=LINE('',#974,#973);
#976=EDGE_CURVE('E291',#948,#828,#975,.T.);
#977=ORIENTED_EDGE('',*,*,#976,.T.);
#978=EDGE_LOOP('',(#969,#970,#971,#977));
#979=FACE_BOUND('',#978,.T.);
#980=ADVANCED_FACE('F327',(#979),#968,.F.);
#981=CARTESIAN_POINT('',(1956.114704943,-330.,420.));
#982=DIRECTION('',(-0.339727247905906,0.94052400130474,0.));
#983=DIRECTION('',(-0.94052400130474,-0.339727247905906,0.));
#984=AXIS2_PLACEMENT_3D('',#981,#982,#983);
#985=PLANE('',#984);
#986=ORIENTED_EDGE('',*,*,#852,.T.);
#987=ORIENTED_EDGE('',*,*,#976,.F.);
#988=DIRECTION('',(0.940478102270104,0.339710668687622,0.00987930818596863));
#989=VECTOR('',#988,1.);
#990=CARTESIAN_POINT('',(1956.114704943,-330.,228.33333333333));
#991=LINE('',#990,#989);
#992=EDGE_CURVE('E287',#948,#556,#991,.T.);
#993=ORIENTED_EDGE('',*,*,#992,.T.);
#994=ORIENTED_EDGE('',*,*,#580,.T.);
#995=EDGE_LOOP('',(#986,#987,#993,#994));
#996=FACE_BOUND('',#995,.T.);
#997=ADVANCED_FACE('F377',(#996),#985,.F.);
#998=CARTESIAN_POINT('',(2432.09849074,-158.06960654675,233.33333333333));
#999=CARTESIAN_POINT('',(2273.437228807,-215.37973769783,231.66666666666));
#1000=CARTESIAN_POINT('',(2114.775966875,-272.68986884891,230.));
#1001=CARTESIAN_POINT('',(1956.114704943,-330.,228.33333333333));
#1002=CARTESIAN_POINT('',(2484.206793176,-158.06960654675,222.22222222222));
#1003=CARTESIAN_POINT('',(2309.692354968,-219.61473779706,221.43592585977));
#1004=CARTESIAN_POINT('',(2135.17791676,-281.15986904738,220.64962949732));
#1005=CARTESIAN_POINT('',(1960.663478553,-342.70500029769,219.86333313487));
#1006=CARTESIAN_POINT('',(2536.315095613,-158.06960654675,211.11111111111));
#1007=CARTESIAN_POINT('',(2345.947481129,-223.8497378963,211.20518505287));
#1008=CARTESIAN_POINT('',(2155.579866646,-289.62986924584,211.29925899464));
#1009=CARTESIAN_POINT('',(1965.212252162,-355.41000059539,211.3933329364));
#1010=CARTESIAN_POINT('',(2588.42339805,-158.06960654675,200.));
#1011=CARTESIAN_POINT('',(2382.20260729,-228.08473799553,200.97444424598));
#1012=CARTESIAN_POINT('',(2175.981816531,-298.0998694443,201.94888849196));
#1013=CARTESIAN_POINT('',(1969.761025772,-368.11500089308,202.92333273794));
#1014=(BOUNDED_SURFACE() B_SPLINE_SURFACE(3,3,((#998,#999,#1000,#1001),(#1002,#1003,#1004,
#1005),(#1006,#1007,#1008,#1009),(#1010,#1011,#1012,#1013)),.UNSPECIFIED.,.F.,.F.,
.F.) B_SPLINE_SURFACE_WITH_KNOTS((4,4),(4,4),(0.,1.),(0.,1.),
.UNSPECIFIED.) GEOMETRIC_REPRESENTATION_ITEM() RATIONAL_B_SPLINE_SURFACE(((1.,1.,1.,1.),(1.,1.,
1.,1.),(1.,1.,1.,1.),(1.,1.,1.,1.))) REPRESENTATION_ITEM('') SURFACE());
#1015=DIRECTION('',(0.946903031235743,0.321488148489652,-0.00447435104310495));
#1016=VECTOR('',#1015,1.);
#1017=CARTESIAN_POINT('',(1969.76102577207,-368.11500089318,202.923332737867));
#1018=LINE('',#1017,#1016);
#1019=EDGE_CURVE('E296',#870,#532,#1018,.T.);
#1020=ORIENTED_EDGE('',*,*,#563,.T.);
#1021=ORIENTED_EDGE('',*,*,#992,.F.);
#1022=ORIENTED_EDGE('',*,*,#949,.T.);
#1023=ORIENTED_EDGE('',*,*,#1019,.T.);
#1024=EDGE_LOOP('',(#1020,#1021,#1022,#1023));
#1025=FACE_BOUND('',#1024,.T.);
#1026=ADVANCED_FACE('F367',(#1025),#1014,.F.);
#1027=CARTESIAN_POINT('',(2279.092211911,-263.09230371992,103.96166636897));
#1028=DIRECTION('',(0.321491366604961,-0.946912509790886,0.));
#1029=DIRECTION('',(0.,0.,-1.));
#1030=AXIS2_PLACEMENT_3D('',#1027,#1028,#1029);
#1031=PLANE('',#1030);
#1032=ORIENTED_EDGE('',*,*,#241,.T.);
#1033=ORIENTED_EDGE('',*,*,#539,.F.);
#1034=ORIENTED_EDGE('',*,*,#1019,.F.);
#1035=ORIENTED_EDGE('',*,*,#871,.F.);
#1036=EDGE_LOOP('',(#1032,#1033,#1034,#1035));
#1037=FACE_BOUND('',#1036,.T.);
#1038=ADVANCED_FACE('F325',(#1037),#1031,.T.);
#1039=CARTESIAN_POINT('',(1517.21004844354,-380.285286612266,-99550.));
#1040=CARTESIAN_POINT('',(1525.68566392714,-369.090983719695,-99550.));
#1041=CARTESIAN_POINT('',(1530.00723404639,-357.168511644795,-99550.));
#1042=CARTESIAN_POINT('',(1530.00000000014,-344.99999999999,-99550.));
#1043=(BOUNDED_CURVE() B_SPLINE_CURVE(3,(#1039,#1040,#1041,#1042),.UNSPECIFIED.,.F.,
.F.) B_SPLINE_CURVE_WITH_KNOTS((4,4),(0.,1.),
.UNSPECIFIED.) CURVE() GEOMETRIC_REPRESENTATION_ITEM() RATIONAL_B_SPLINE_CURVE((1.,
0.986520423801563,0.986520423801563,1.)) REPRESENTATION_ITEM(''));
#1044=DIRECTION('',(0.,0.,1.));
#1045=VECTOR('',#1044,1.);
#1046=SURFACE_OF_LINEAR_EXTRUSION('',#1043,#1045);
#1047=ORIENTED_EDGE('',*,*,#937,.F.);
#1048=ORIENTED_EDGE('',*,*,#615,.F.);
#1049=CARTESIAN_POINT('',(1369.98303290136,-344.999999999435,164.99999999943));
#1050=DIRECTION('',(0.,-0.707106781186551,-0.707106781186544));
#1051=DIRECTION('',(0.999999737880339,-0.000511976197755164,0.000511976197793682));
#1052=AXIS2_PLACEMENT_3D('',#1049,#1050,#1051);
#1053=ELLIPSE('',#1052,160.016991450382,127.279203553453);
#1054=EDGE_CURVE('E680',#606,#936,#1053,.T.);
#1055=ORIENTED_EDGE('',*,*,#1054,.T.);
#1056=EDGE_LOOP('',(#1047,#1048,#1055));
#1057=FACE_BOUND('',#1056,.T.);
#1058=ADVANCED_FACE('F319',(#1057),#1046,.F.);
#1059=CARTESIAN_POINT('',(1480.,-330.,0.));
#1060=DIRECTION('',(0.,1.,0.));
#1061=DIRECTION('',(0.,0.,-1.));
#1062=AXIS2_PLACEMENT_3D('',#1059,#1060,#1061);
#1063=PLANE('',#1062);
#1064=DIRECTION('',(-1.,0.,0.));
#1065=VECTOR('',#1064,1.);
#1066=CARTESIAN_POINT('',(885.,-330.,150.));
#1067=LINE('',#1066,#1065);
#1068=EDGE_CURVE('E250',#598,#777,#1067,.T.);
#1069=ORIENTED_EDGE('',*,*,#1068,.F.);
#1070=ORIENTED_EDGE('',*,*,#599,.T.);
#1071=ORIENTED_EDGE('',*,*,#265,.F.);
#1072=ORIENTED_EDGE('',*,*,#786,.T.);
#1073=EDGE_LOOP('',(#1069,#1070,#1071,#1072));
#1074=FACE_BOUND('',#1073,.T.);
#1075=ADVANCED_FACE('F324',(#1074),#1063,.T.);
#1076=CARTESIAN_POINT('',(885.,-96.654762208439,-83.34523779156));
#1077=DIRECTION('',(0.,0.707106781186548,0.707106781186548));
#1078=DIRECTION('',(-1.,0.,0.));
#1079=AXIS2_PLACEMENT_3D('',#1076,#1077,#1078);
#1080=PLANE('',#1079);
#1081=ORIENTED_EDGE('',*,*,#942,.T.);
#1082=ORIENTED_EDGE('',*,*,#1054,.F.);
#1083=ORIENTED_EDGE('',*,*,#607,.F.);
#1084=ORIENTED_EDGE('',*,*,#1068,.T.);
#1085=ORIENTED_EDGE('',*,*,#780,.T.);
#1086=EDGE_LOOP('',(#1081,#1082,#1083,#1084,#1085));
#1087=FACE_BOUND('',#1086,.T.);
#1088=ADVANCED_FACE('F394',(#1087),#1080,.T.);
#1089=CLOSED_SHELL('',(#50,#81,#129,#172,#219,#298,#315,#339,#422,#444,#468,#504,#521,#545,#569,
#586,#676,#696,#713,#726,#742,#766,#805,#841,#858,#882,#963,#980,#997,#1026,#1038,#1058,#1075,#1088));
#1090=MANIFOLD_SOLID_BREP('B2',#1089);
#1091=ADVANCED_BREP_SHAPE_REPRESENTATION('',(#18,#1090),#14);
#1092=SHAPE_DEFINITION_REPRESENTATION(#9,#1091);
ENDSEC;
END-ISO-10303-21;
